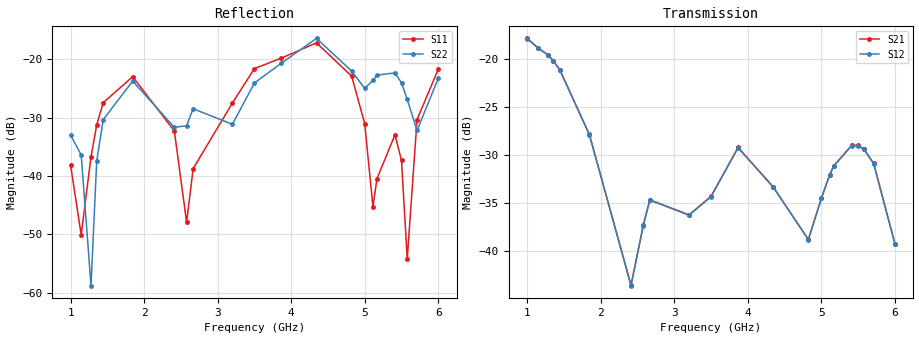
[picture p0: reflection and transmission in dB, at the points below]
!Agilent Technologies,E8364B,MY43040528,A.07.50.67
!Agilent E8364B: A.07.50.67
!Date: Sunday, March 01, 2026 17:06:43
!Correction: S11(Full 2 Port(1,2))
!S21(Full 2 Port(1,2))
!S12(Full 2 Port(1,2))
!S22(Full 2 Port(1,2))
!S2P File: Measurements: S11, S21, S12, S22:
# Hz S  dB  R 50
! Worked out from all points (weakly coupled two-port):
!   451 points, 1 GHz to 6 GHz, reference 50 ohm
!   highest |S21| = -17.81 dB at 1 GHz (marker M1); lowest = -43.6 dB at 2.411 GHz (marker M2)
!   lowest |S11| = -54.3 dB at 5.578 GHz (marker M3), VSWR 1.00, Z = 50.1 - j0.14 ohm
!   |S11| at or under -10 dB: start of sweep to end of sweep
!   |S22| runs from -58.8 to -16.4 dB; largest |S21 - S12| = 0.00057
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1e9  -38.12 7.3  -17.81 28.4  -17.85 28.5  -33.01 -3.2
1.144444e9  -50.10 -61.2  -18.78 -14.5  -18.82 -14.5  -36.39 -6.5
1.277778e9  -36.75 -141.3  -19.50 -57.0  -19.54 -57.0  -58.80 17.9
1.355556e9  -31.23 -160.1  -20.13 -83.2  -20.16 -83.1  -37.42 118.3
1.444444e9  -27.44 176.3  -21.11 -113.2  -21.15 -113.2  -30.35 96.1
1.844444e9  -23.00 88.8  -27.83 119.2  -27.87 119.2  -23.74 -4.4
2.411111e9  -32.30 -15.6  -43.58 -128.5  -43.64 -128.4  -31.67 -79.9
2.577778e9  -47.93 -134.0  -37.33 109.7  -37.37 109.8  -31.39 -53.0
2.666667e9  -38.74 138.2  -34.67 67.6  -34.71 67.7  -28.48 -57.4
3.2e9  -27.52 117.7  -36.24 -127.6  -36.28 -127.5  -31.16 -117.8
3.5e9  -21.60 67.7  -34.30 -157.0  -34.34 -156.9  -24.07 -129.1
3.866667e9  -19.81 27.6  -29.20 74.4  -29.24 74.5  -20.68 -165.6
4.344444e9  -17.20 -48.4  -33.31 -102.2  -33.35 -102.2  -16.43 111.4
4.822222e9  -22.91 -140.2  -38.80 21.2  -38.84 21.3  -22.04 34.0
5e9  -31.06 -175.2  -34.49 -80.5  -34.53 -80.5  -25.00 37.9
5.111111e9  -45.24 -142.6  -32.07 -134.1  -32.11 -134.1  -23.63 39.4
5.166667e9  -40.45 -72.8  -31.13 -159.4  -31.17 -159.4  -22.72 34.0
5.411111e9  -32.95 -113.1  -28.98 93.6  -29.02 93.6  -22.35 -12.2
5.5e9  -37.35 -128.6  -28.99 55.5  -29.03 55.5  -24.06 -30.3
5.577778e9  -54.25 -46.2  -29.36 22.5  -29.40 22.4  -26.89 -40.2
5.711111e9  -30.36 -15.7  -30.87 -33.1  -30.92 -33.1  -32.20 -16.4
6e9  -21.70 -75.2  -39.26 -136.3  -39.30 -136.4  -23.29 -16.4
